VERSION 5.7 ;
  NOWIREEXTENSIONATPIN ON ;
  DIVIDERCHAR "/" ;
  BUSBITCHARS "[]" ;
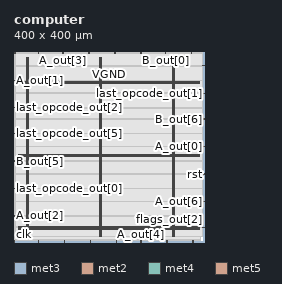
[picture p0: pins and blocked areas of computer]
MACRO computer
  CLASS BLOCK ;
  FOREIGN computer ;
  ORIGIN 0.000 0.000 ;
  SIZE 400.000 BY 400.000 ;
  PIN A_out[0]
    DIRECTION OUTPUT TRISTATE ;
    USE SIGNAL ;
    ANTENNADIFFAREA 0.795200 ;
    PORT
      LAYER met3 ;
        RECT 396.000 200.640 400.000 201.240 ;
    END
  END A_out[0]
  PIN A_out[1]
    DIRECTION OUTPUT TRISTATE ;
    USE SIGNAL ;
    ANTENNADIFFAREA 0.795200 ;
    PORT
      LAYER met3 ;
        RECT 0.000 340.040 4.000 340.640 ;
    END
  END A_out[1]
  PIN A_out[2]
    DIRECTION OUTPUT TRISTATE ;
    USE SIGNAL ;
    ANTENNADIFFAREA 0.795200 ;
    PORT
      LAYER met3 ;
        RECT 0.000 54.440 4.000 55.040 ;
    END
  END A_out[2]
  PIN A_out[3]
    DIRECTION OUTPUT TRISTATE ;
    USE SIGNAL ;
    ANTENNADIFFAREA 0.795200 ;
    PORT
      LAYER met2 ;
        RECT 103.130 396.000 103.410 400.000 ;
    END
  END A_out[3]
  PIN A_out[4]
    DIRECTION OUTPUT TRISTATE ;
    USE SIGNAL ;
    ANTENNADIFFAREA 0.795200 ;
    PORT
      LAYER met2 ;
        RECT 267.350 0.000 267.630 4.000 ;
    END
  END A_out[4]
  PIN A_out[5]
    DIRECTION OUTPUT TRISTATE ;
    USE SIGNAL ;
    ANTENNADIFFAREA 0.445500 ;
    PORT
      LAYER met2 ;
        RECT 51.610 396.000 51.890 400.000 ;
    END
  END A_out[5]
  PIN A_out[6]
    DIRECTION OUTPUT TRISTATE ;
    USE SIGNAL ;
    ANTENNADIFFAREA 0.445500 ;
    PORT
      LAYER met3 ;
        RECT 396.000 85.040 400.000 85.640 ;
    END
  END A_out[6]
  PIN A_out[7]
    DIRECTION OUTPUT TRISTATE ;
    USE SIGNAL ;
    ANTENNADIFFAREA 0.795200 ;
    PORT
      LAYER met2 ;
        RECT 157.870 396.000 158.150 400.000 ;
    END
  END A_out[7]
  PIN B_out[0]
    DIRECTION OUTPUT TRISTATE ;
    USE SIGNAL ;
    ANTENNADIFFAREA 0.795200 ;
    PORT
      LAYER met2 ;
        RECT 318.870 396.000 319.150 400.000 ;
    END
  END B_out[0]
  PIN B_out[1]
    DIRECTION OUTPUT TRISTATE ;
    USE SIGNAL ;
    ANTENNADIFFAREA 0.795200 ;
    PORT
      LAYER met2 ;
        RECT 322.090 0.000 322.370 4.000 ;
    END
  END B_out[1]
  PIN B_out[2]
    DIRECTION OUTPUT TRISTATE ;
    USE SIGNAL ;
    ANTENNADIFFAREA 0.445500 ;
    PORT
      LAYER met3 ;
        RECT 396.000 370.640 400.000 371.240 ;
    END
  END B_out[2]
  PIN B_out[3]
    DIRECTION OUTPUT TRISTATE ;
    USE SIGNAL ;
    ANTENNADIFFAREA 0.795200 ;
    PORT
      LAYER met2 ;
        RECT 267.350 396.000 267.630 400.000 ;
    END
  END B_out[3]
  PIN B_out[4]
    DIRECTION OUTPUT TRISTATE ;
    USE SIGNAL ;
    ANTENNADIFFAREA 0.795200 ;
    PORT
      LAYER met2 ;
        RECT 373.610 396.000 373.890 400.000 ;
    END
  END B_out[4]
  PIN B_out[5]
    DIRECTION OUTPUT TRISTATE ;
    USE SIGNAL ;
    ANTENNADIFFAREA 0.795200 ;
    PORT
      LAYER met3 ;
        RECT 0.000 170.040 4.000 170.640 ;
    END
  END B_out[5]
  PIN B_out[6]
    DIRECTION OUTPUT TRISTATE ;
    USE SIGNAL ;
    ANTENNADIFFAREA 0.445500 ;
    PORT
      LAYER met3 ;
        RECT 396.000 258.440 400.000 259.040 ;
    END
  END B_out[6]
  PIN B_out[7]
    DIRECTION OUTPUT TRISTATE ;
    USE SIGNAL ;
    ANTENNADIFFAREA 0.795200 ;
    PORT
      LAYER met2 ;
        RECT 376.830 0.000 377.110 4.000 ;
    END
  END B_out[7]
  PIN VGND
    DIRECTION INOUT ;
    USE GROUND ;
    PORT
      LAYER met4 ;
        RECT 28.940 10.640 30.540 389.200 ;
    END
    PORT
      LAYER met4 ;
        RECT 182.540 10.640 184.140 389.200 ;
    END
    PORT
      LAYER met4 ;
        RECT 336.140 10.640 337.740 389.200 ;
    END
    PORT
      LAYER met5 ;
        RECT 9.880 30.030 389.860 31.630 ;
    END
    PORT
      LAYER met5 ;
        RECT 9.880 183.210 389.860 184.810 ;
    END
    PORT
      LAYER met5 ;
        RECT 9.880 336.390 389.860 337.990 ;
    END
  END VGND
  PIN VPWR
    DIRECTION INOUT ;
    USE POWER ;
    PORT
      LAYER met4 ;
        RECT 25.640 10.640 27.240 389.200 ;
    END
    PORT
      LAYER met4 ;
        RECT 179.240 10.640 180.840 389.200 ;
    END
    PORT
      LAYER met4 ;
        RECT 332.840 10.640 334.440 389.200 ;
    END
    PORT
      LAYER met5 ;
        RECT 9.880 26.730 389.860 28.330 ;
    END
    PORT
      LAYER met5 ;
        RECT 9.880 179.910 389.860 181.510 ;
    END
    PORT
      LAYER met5 ;
        RECT 9.880 333.090 389.860 334.690 ;
    END
  END VPWR
  PIN clk
    DIRECTION INPUT ;
    USE SIGNAL ;
    ANTENNAGATEAREA 0.852000 ;
    PORT
      LAYER met2 ;
        RECT 0.090 0.000 0.370 4.000 ;
    END
  END clk
  PIN flags_out[0]
    DIRECTION OUTPUT TRISTATE ;
    USE SIGNAL ;
    ANTENNADIFFAREA 0.795200 ;
    PORT
      LAYER met2 ;
        RECT 51.610 0.000 51.890 4.000 ;
    END
  END flags_out[0]
  PIN flags_out[1]
    DIRECTION OUTPUT TRISTATE ;
    USE SIGNAL ;
    ANTENNADIFFAREA 0.795200 ;
    PORT
      LAYER met2 ;
        RECT 106.350 0.000 106.630 4.000 ;
    END
  END flags_out[1]
  PIN flags_out[2]
    DIRECTION OUTPUT TRISTATE ;
    USE SIGNAL ;
    ANTENNADIFFAREA 0.445500 ;
    PORT
      LAYER met3 ;
        RECT 396.000 30.640 400.000 31.240 ;
    END
  END flags_out[2]
  PIN flags_out[3]
    DIRECTION OUTPUT TRISTATE ;
    USE SIGNAL ;
    ANTENNADIFFAREA 0.795200 ;
    PORT
      LAYER met2 ;
        RECT 161.090 0.000 161.370 4.000 ;
    END
  END flags_out[3]
  PIN last_opcode_out[0]
    DIRECTION OUTPUT TRISTATE ;
    USE SIGNAL ;
    ANTENNADIFFAREA 0.795200 ;
    PORT
      LAYER met3 ;
        RECT 0.000 112.240 4.000 112.840 ;
    END
  END last_opcode_out[0]
  PIN last_opcode_out[1]
    DIRECTION OUTPUT TRISTATE ;
    USE SIGNAL ;
    ANTENNADIFFAREA 0.445500 ;
    PORT
      LAYER met3 ;
        RECT 396.000 312.840 400.000 313.440 ;
    END
  END last_opcode_out[1]
  PIN last_opcode_out[2]
    DIRECTION OUTPUT TRISTATE ;
    USE SIGNAL ;
    ANTENNADIFFAREA 0.795200 ;
    PORT
      LAYER met3 ;
        RECT 0.000 282.240 4.000 282.840 ;
    END
  END last_opcode_out[2]
  PIN last_opcode_out[3]
    DIRECTION OUTPUT TRISTATE ;
    USE SIGNAL ;
    ANTENNADIFFAREA 0.795200 ;
    PORT
      LAYER met2 ;
        RECT 212.610 396.000 212.890 400.000 ;
    END
  END last_opcode_out[3]
  PIN last_opcode_out[4]
    DIRECTION OUTPUT TRISTATE ;
    USE SIGNAL ;
    ANTENNADIFFAREA 0.795200 ;
    PORT
      LAYER met2 ;
        RECT 215.830 0.000 216.110 4.000 ;
    END
  END last_opcode_out[4]
  PIN last_opcode_out[5]
    DIRECTION OUTPUT TRISTATE ;
    USE SIGNAL ;
    PORT
      LAYER met3 ;
        RECT 0.000 227.840 4.000 228.440 ;
    END
  END last_opcode_out[5]
  PIN last_opcode_out[6]
    DIRECTION OUTPUT TRISTATE ;
    USE SIGNAL ;
    ANTENNADIFFAREA 0.795200 ;
    PORT
      LAYER met3 ;
        RECT 0.000 397.840 4.000 398.440 ;
    END
  END last_opcode_out[6]
  PIN rst
    DIRECTION INPUT ;
    USE SIGNAL ;
    ANTENNAGATEAREA 0.196500 ;
    PORT
      LAYER met3 ;
        RECT 396.000 142.840 400.000 143.440 ;
    END
  END rst
  OBS
      LAYER li1 ;
        RECT 10.120 10.795 389.620 389.045 ;
      LAYER met1 ;
        RECT 0.070 10.640 392.310 389.200 ;
      LAYER met2 ;
        RECT 0.100 395.720 51.330 398.325 ;
        RECT 52.170 395.720 102.850 398.325 ;
        RECT 103.690 395.720 157.590 398.325 ;
        RECT 158.430 395.720 212.330 398.325 ;
        RECT 213.170 395.720 267.070 398.325 ;
        RECT 267.910 395.720 318.590 398.325 ;
        RECT 319.430 395.720 373.330 398.325 ;
        RECT 374.170 395.720 392.290 398.325 ;
        RECT 0.100 4.280 392.290 395.720 ;
        RECT 0.650 3.670 51.330 4.280 ;
        RECT 52.170 3.670 106.070 4.280 ;
        RECT 106.910 3.670 160.810 4.280 ;
        RECT 161.650 3.670 215.550 4.280 ;
        RECT 216.390 3.670 267.070 4.280 ;
        RECT 267.910 3.670 321.810 4.280 ;
        RECT 322.650 3.670 376.550 4.280 ;
        RECT 377.390 3.670 392.290 4.280 ;
      LAYER met3 ;
        RECT 4.400 397.440 396.000 398.305 ;
        RECT 4.000 371.640 396.000 397.440 ;
        RECT 4.000 370.240 395.600 371.640 ;
        RECT 4.000 341.040 396.000 370.240 ;
        RECT 4.400 339.640 396.000 341.040 ;
        RECT 4.000 313.840 396.000 339.640 ;
        RECT 4.000 312.440 395.600 313.840 ;
        RECT 4.000 283.240 396.000 312.440 ;
        RECT 4.400 281.840 396.000 283.240 ;
        RECT 4.000 259.440 396.000 281.840 ;
        RECT 4.000 258.040 395.600 259.440 ;
        RECT 4.000 228.840 396.000 258.040 ;
        RECT 4.400 227.440 396.000 228.840 ;
        RECT 4.000 201.640 396.000 227.440 ;
        RECT 4.000 200.240 395.600 201.640 ;
        RECT 4.000 171.040 396.000 200.240 ;
        RECT 4.400 169.640 396.000 171.040 ;
        RECT 4.000 143.840 396.000 169.640 ;
        RECT 4.000 142.440 395.600 143.840 ;
        RECT 4.000 113.240 396.000 142.440 ;
        RECT 4.400 111.840 396.000 113.240 ;
        RECT 4.000 86.040 396.000 111.840 ;
        RECT 4.000 84.640 395.600 86.040 ;
        RECT 4.000 55.440 396.000 84.640 ;
        RECT 4.400 54.040 396.000 55.440 ;
        RECT 4.000 31.640 396.000 54.040 ;
        RECT 4.000 30.240 395.600 31.640 ;
        RECT 4.000 10.715 396.000 30.240 ;
  END
END computer
END LIBRARY

